##
## LEF for PtnCells ;
## created by Innovus v20.10-p004_1 on Sun Oct 11 11:27:30 2026
##

VERSION 5.8 ;

BUSBITCHARS "[]" ;
DIVIDERCHAR "/" ;

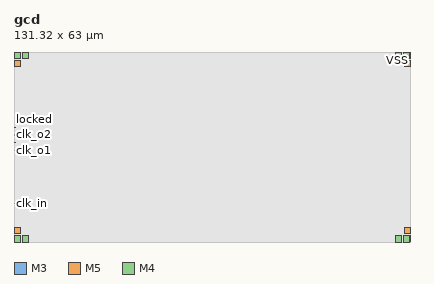
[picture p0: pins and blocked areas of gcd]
MACRO gcd
  CLASS BLOCK ;
  SIZE 131.320000 BY 63.000000 ;
  FOREIGN gcd 0.000000 0.000000 ;
  ORIGIN 0 0 ;
  SYMMETRY X Y R90 ;
  PIN clk_in
    DIRECTION INPUT ;
    USE SIGNAL ;
    ANTENNAPARTIALMETALAREA 20.1768 LAYER M3  ;
    ANTENNAPARTIALMETALSIDEAREA 0.14538 LAYER M3  ;
    ANTENNAMODEL OXIDE1 ;
    ANTENNAGATEAREA 3.356 LAYER M3  ;
    ANTENNAMAXAREACAR 38.3942 LAYER M3  ;
    ANTENNAMAXSIDEAREACAR 0.297688 LAYER M3  ;
    ANTENNAPARTIALCUTAREA 0.0169 LAYER VIA3  ;
    ANTENNAMAXCUTCAR 0.957732 LAYER VIA3  ;
    ANTENNAPARTIALMETALAREA 4.4618 LAYER M4  ;
    ANTENNAPARTIALMETALSIDEAREA 0.03201 LAYER M4  ;
    ANTENNAGATEAREA 3.416 LAYER M4  ;
    ANTENNAMAXAREACAR 39.7003 LAYER M4  ;
    ANTENNAMAXSIDEAREACAR 0.307058 LAYER M4  ;
    ANTENNAMAXCUTCAR 0.957732 LAYER VIA4  ;
    PORT
      LAYER M3 ;
        RECT 0.000000 12.670000 0.500000 12.810000 ;
    END
  END clk_in
  PIN rst_n
    DIRECTION INPUT ;
    USE SIGNAL ;
    ANTENNAPARTIALMETALAREA 19.4901 LAYER M3  ;
    ANTENNAPARTIALMETALSIDEAREA 0.140195 LAYER M3  ;
    ANTENNAMODEL OXIDE1 ;
    ANTENNAGATEAREA 4.164 LAYER M3  ;
    ANTENNAMAXAREACAR 21.2656 LAYER M3  ;
    ANTENNAMAXSIDEAREACAR 0.156568 LAYER M3  ;
    ANTENNAMAXCUTCAR 0.492838 LAYER VIA3  ;
    PORT
      LAYER M3 ;
        RECT 0.000000 35.350000 0.500000 35.490000 ;
    END
  END rst_n
  PIN clk_o1
    DIRECTION OUTPUT ;
    USE SIGNAL ;
    ANTENNADIFFAREA 0.2282 LAYER M3  ;
    ANTENNAPARTIALMETALAREA 2.4283 LAYER M3  ;
    ANTENNAPARTIALMETALSIDEAREA 0.017485 LAYER M3  ;
    ANTENNAMODEL OXIDE1 ;
    ANTENNAGATEAREA 0.114 LAYER M3  ;
    ANTENNAMAXAREACAR 26.98 LAYER M3  ;
    ANTENNAMAXSIDEAREACAR 0.194254 LAYER M3  ;
    ANTENNAMAXCUTCAR 0.444737 LAYER VIA3  ;
    PORT
      LAYER M3 ;
        RECT 0.000000 30.310000 0.500000 30.450000 ;
    END
  END clk_o1
  PIN clk_o2
    DIRECTION OUTPUT ;
    USE SIGNAL ;
    ANTENNADIFFAREA 0.2282 LAYER M3  ;
    ANTENNAPARTIALMETALAREA 4.6249 LAYER M3  ;
    ANTENNAPARTIALMETALSIDEAREA 0.033175 LAYER M3  ;
    ANTENNAMODEL OXIDE1 ;
    ANTENNAGATEAREA 0.114 LAYER M3  ;
    ANTENNAMAXAREACAR 46.2485 LAYER M3  ;
    ANTENNAMAXSIDEAREACAR 0.331886 LAYER M3  ;
    ANTENNAMAXCUTCAR 0.444737 LAYER VIA3  ;
    PORT
      LAYER M3 ;
        RECT 0.000000 32.830000 0.500000 32.970000 ;
    END
  END clk_o2
  PIN locked
    DIRECTION OUTPUT ;
    USE SIGNAL ;
    ANTENNADIFFAREA 0.3302 LAYER M3  ;
    ANTENNAPARTIALMETALAREA 0.3591 LAYER M3  ;
    ANTENNAPARTIALMETALSIDEAREA 0.002565 LAYER M3  ;
    PORT
      LAYER M3 ;
        RECT 0.000000 37.870000 0.500000 38.010000 ;
    END
  END locked
  PIN VDD
    DIRECTION INOUT ;
    USE POWER ;
    PORT
      LAYER M5 ;
        RECT 129.320000 58.230000 131.320000 60.230000 ;
    END
    PORT
      LAYER M5 ;
        RECT 0.000000 58.230000 2.000000 60.230000 ;
    END
    PORT
      LAYER M5 ;
        RECT 129.320000 2.770000 131.320000 4.770000 ;
    END
    PORT
      LAYER M5 ;
        RECT 0.000000 2.770000 2.000000 4.770000 ;
    END
    PORT
      LAYER M4 ;
        RECT 126.550000 61.000000 128.550000 63.000000 ;
    END
    PORT
      LAYER M4 ;
        RECT 126.550000 0.000000 128.550000 2.000000 ;
    END
    PORT
      LAYER M4 ;
        RECT 2.770000 61.000000 4.770000 63.000000 ;
    END
    PORT
      LAYER M4 ;
        RECT 2.770000 0.000000 4.770000 2.000000 ;
    END
  END VDD
  PIN VSS
    DIRECTION INOUT ;
    USE GROUND ;
    PORT
      LAYER M5 ;
        RECT 129.320000 60.730000 131.320000 62.730000 ;
    END
    PORT
      LAYER M5 ;
        RECT 0.000000 60.730000 2.000000 62.730000 ;
    END
    PORT
      LAYER M5 ;
        RECT 129.320000 0.270000 131.320000 2.270000 ;
    END
    PORT
      LAYER M5 ;
        RECT 0.000000 0.270000 2.000000 2.270000 ;
    END
    PORT
      LAYER M4 ;
        RECT 129.050000 61.000000 131.050000 63.000000 ;
    END
    PORT
      LAYER M4 ;
        RECT 129.050000 0.000000 131.050000 2.000000 ;
    END
    PORT
      LAYER M4 ;
        RECT 0.270000 61.000000 2.270000 63.000000 ;
    END
    PORT
      LAYER M4 ;
        RECT 0.270000 0.000000 2.270000 2.000000 ;
    END
  END VSS
  OBS
    LAYER M1 ;
      RECT 0.000000 0.000000 131.320000 63.000000 ;
    LAYER M2 ;
      RECT 0.000000 0.000000 131.320000 63.000000 ;
    LAYER M3 ;
      RECT 0.000000 39.510000 131.320000 63.000000 ;
      RECT 2.000000 28.810000 131.320000 39.510000 ;
      RECT 0.000000 14.310000 131.320000 28.810000 ;
      RECT 2.000000 11.170000 131.320000 14.310000 ;
      RECT 0.000000 0.000000 131.320000 11.170000 ;
    LAYER M4 ;
      RECT 6.270000 59.500000 125.050000 63.000000 ;
      RECT 0.000000 3.500000 131.320000 59.500000 ;
      RECT 6.270000 0.000000 125.050000 3.500000 ;
    LAYER M5 ;
      RECT 3.500000 56.730000 127.820000 63.000000 ;
      RECT 0.000000 6.270000 131.320000 56.730000 ;
      RECT 3.500000 0.000000 127.820000 6.270000 ;
    LAYER M6 ;
      RECT 0.000000 0.000000 131.320000 63.000000 ;
    LAYER M7 ;
      RECT 0.000000 0.000000 131.320000 63.000000 ;
    LAYER M8 ;
      RECT 0.000000 0.000000 131.320000 63.000000 ;
  END
END gcd

END LIBRARY
